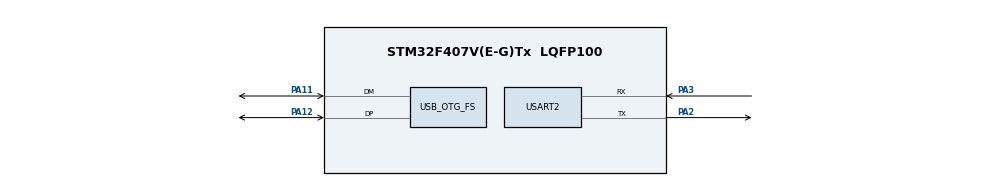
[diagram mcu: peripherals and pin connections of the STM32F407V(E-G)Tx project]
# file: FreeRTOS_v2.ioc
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FREERTOS.Tasks01=defaultTask,0,128,StartDefaultTask,Default,NULL,Dynamic,NULL,NULL
Mcu.Family=STM32F4
Mcu.Name=STM32F407V(E-G)Tx
Mcu.Package=LQFP100
NVIC.OTG_FS_IRQn=true\:5\:0\:false\:false\:true\:true\:false\:true\:true
NVIC.PriorityGroup=NVIC_PRIORITYGROUP_4
NVIC.TIM1_UP_TIM10_IRQn=true\:15\:0\:false\:false\:true\:false\:false\:true\:true
NVIC.TimeBase=TIM1_UP_TIM10_IRQn
NVIC.TimeBaseIP=TIM1
PA11.Mode=Device_Only
PA11.Signal=USB_OTG_FS_DM
PA12.Mode=Device_Only
PA12.Signal=USB_OTG_FS_DP
PA2.Mode=Asynchronous
PA2.Signal=USART2_TX
PA3.Mode=Asynchronous
PA3.Signal=USART2_RX
PC14-OSC32_IN.Mode=LSE-External-Oscillator
PC14-OSC32_IN.Signal=RCC_OSC32_IN
PC15-OSC32_OUT.Mode=LSE-External-Oscillator
PC15-OSC32_OUT.Signal=RCC_OSC32_OUT
PH0-OSC_IN.Mode=HSE-External-Oscillator
PH0-OSC_IN.Signal=RCC_OSC_IN
PH1-OSC_OUT.Mode=HSE-External-Oscillator
PH1-OSC_OUT.Signal=RCC_OSC_OUT
ProjectManager.HeapSize=0x200
ProjectManager.StackSize=0x400
ProjectManager.TargetToolchain=STM32CubeIDE
RCC.48MHZClocksFreq_Value=48000000
RCC.AHBFreq_Value=16000000
RCC.APB1Freq_Value=16000000
RCC.APB2Freq_Value=16000000
RCC.CortexFreq_Value=16000000
RCC.HSE_VALUE=8000000
RCC.HSI_VALUE=16000000
RCC.PLLM=4
RCC.PLLN=72
RCC.PLLQ=3
RCC.SYSCLKFreq_VALUE=16000000
RCC.VCOOutputFreq_Value=144000000
USART2.VirtualMode=VM_ASYNC
USB_DEVICE.CLASS_NAME_FS=CDC
USB_DEVICE.VirtualMode-CDC_FS=Cdc
USB_DEVICE.VirtualModeFS=Cdc_FS
USB_OTG_FS.VirtualMode=Device_Only
VP_FREERTOS_VS_CMSIS_V1.Mode=CMSIS_V1
VP_SYS_VS_tim1.Mode=TIM1
VP_USB_DEVICE_VS_USB_DEVICE_CDC_FS.Mode=CDC_FS
board=custom

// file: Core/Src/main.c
/* USER CODE BEGIN Header */
/**
  ******************************************************************************
  * @file           : main.c
  * @brief          : Main program body
  ******************************************************************************
  * @attention
  *
  * Copyright (c) 2026 STMicroelectronics.
  * All rights reserved.
  *
  * This software is licensed under terms that can be found in the LICENSE file
  * in the root directory of this software component.
  * If no LICENSE file comes with this software, it is provided AS-IS.
  *
  ******************************************************************************
  */

#include <stdio.h>
#include "uart.h"
#include "adc.h"
#include "exti.h"

/* USER CODE END Header */
#include "main.h"
#include "cmsis_os.h"
#include "usb_device.h"

/* USER CODE BEGIN PV */

/* Definitions for defaultTask */

/* USER CODE END PV */

void SystemClock_Config(void);
static void MX_GPIO_Init(void);

/* USER CODE BEGIN 0 */
void ADC_Task(void *pvParameters);
TaskHandle_t receiver_handle;
/* USER CODE END 0 */

int main(void)
{

  /* MCU Configuration--------------------------------------------------------*/

  /* Reset of all peripherals, Initializes the Flash interface and the Systick. */
  HAL_Init();

  /* Configure the system clock */
  SystemClock_Config();

  /* Initialize all configured peripherals */
  MX_GPIO_Init();
  MX_USART2_UART_TX_Init();
  MX_USART2_UART_RX_Init();
  /* USER CODE BEGIN 2 */
  MX_USB_DEVICE_Init();
  gpio_init();

  dmaSemaphore=xSemaphoreCreateBinary();

  adc_init();

  xTaskCreate(ADC_Task,"Receiver Task",500,NULL,2,&receiver_handle);
  vTaskStartScheduler();

  /* USER CODE END 2 */

  /* Create the thread(s) */

  /* Start scheduler */

  /* We should never get here as control is now taken by the scheduler */

  /* Infinite loop */
  while (1)
  {

  }
}

void SystemClock_Config(void)
{
  RCC_OscInitTypeDef RCC_OscInitStruct = {0};
  RCC_ClkInitTypeDef RCC_ClkInitStruct = {0};

  /** Configure the main internal regulator output voltage
  */
  __HAL_RCC_PWR_CLK_ENABLE();
  __HAL_PWR_VOLTAGESCALING_CONFIG(PWR_REGULATOR_VOLTAGE_SCALE1);

  /** Initializes the RCC Oscillators according to the specified parameters
  * in the RCC_OscInitTypeDef structure.
  */
  RCC_OscInitStruct.OscillatorType = RCC_OSCILLATORTYPE_HSI|RCC_OSCILLATORTYPE_HSE;
  RCC_OscInitStruct.HSEState = RCC_HSE_ON;
  RCC_OscInitStruct.HSIState = RCC_HSI_ON;
  RCC_OscInitStruct.HSICalibrationValue = RCC_HSICALIBRATION_DEFAULT;
  RCC_OscInitStruct.PLL.PLLState = RCC_PLL_ON;
  RCC_OscInitStruct.PLL.PLLSource = RCC_PLLSOURCE_HSE;
  RCC_OscInitStruct.PLL.PLLM = 4;
  RCC_OscInitStruct.PLL.PLLN = 72;
  RCC_OscInitStruct.PLL.PLLP = RCC_PLLP_DIV2;
  RCC_OscInitStruct.PLL.PLLQ = 3;
  if (HAL_RCC_OscConfig(&RCC_OscInitStruct) != HAL_OK)
  {
    Error_Handler();
  }

  /** Initializes the CPU, AHB and APB buses clocks
  */
  RCC_ClkInitStruct.ClockType = RCC_CLOCKTYPE_HCLK|RCC_CLOCKTYPE_SYSCLK
                              |RCC_CLOCKTYPE_PCLK1|RCC_CLOCKTYPE_PCLK2;
  RCC_ClkInitStruct.SYSCLKSource = RCC_SYSCLKSOURCE_PLLCLK;
  RCC_ClkInitStruct.AHBCLKDivider = RCC_SYSCLK_DIV1;
  RCC_ClkInitStruct.APB1CLKDivider = RCC_HCLK_DIV1;
  RCC_ClkInitStruct.APB2CLKDivider = RCC_HCLK_DIV1;

  if (HAL_RCC_ClockConfig(&RCC_ClkInitStruct, FLASH_LATENCY_2) != HAL_OK)
  {
    Error_Handler();
  }
}

static void MX_GPIO_Init(void)
{
  /* USER CODE BEGIN MX_GPIO_Init_1 */
	GPIO_InitTypeDef GPIO_InitStruct;
  /* USER CODE END MX_GPIO_Init_1 */

  /* GPIO Ports Clock Enable */
  __HAL_RCC_GPIOC_CLK_ENABLE();
  __HAL_RCC_GPIOH_CLK_ENABLE();
  __HAL_RCC_GPIOA_CLK_ENABLE();

  /* USER CODE BEGIN MX_GPIO_Init_2 */
  /* Enable Clock  access to port */
  __HAL_RCC_GPIOD_CLK_ENABLE();
  /* Reset PINS */
  HAL_GPIO_WritePin(GPIOD,GPIO_PIN_12|GPIO_PIN_13|GPIO_PIN_14|GPIO_PIN_15,GPIO_PIN_RESET);
  /* Configure PINS */
  GPIO_InitStruct.Pin = GPIO_PIN_12|GPIO_PIN_13|GPIO_PIN_14|GPIO_PIN_15;
  GPIO_InitStruct.Speed = GPIO_SPEED_FREQ_LOW;
  GPIO_InitStruct.Mode = GPIO_MODE_OUTPUT_PP;
  GPIO_InitStruct.Pull = GPIO_NOPULL;

  /* Initialize PINS */
  HAL_GPIO_Init(GPIOD, &GPIO_InitStruct);
  /* USER CODE END MX_GPIO_Init_2 */
}

  /* init code for USB_DEVICE */
  /* USER CODE END 5 */

void HAL_TIM_PeriodElapsedCallback(TIM_HandleTypeDef *htim)
{
  if (htim->Instance == TIM1)
  {
    HAL_IncTick();
  }
}

void Error_Handler(void)
{
  __disable_irq();
  while (1)
  {
  }
}

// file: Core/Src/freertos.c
/* USER CODE BEGIN Header */
/**
  ******************************************************************************
  * File Name          : freertos.c
  * Description        : Code for freertos applications
  ******************************************************************************
  * @attention
  *
  * Copyright (c) 2026 STMicroelectronics.
  * All rights reserved.
  *
  * This software is licensed under terms that can be found in the LICENSE file
  * in the root directory of this software component.
  * If no LICENSE file comes with this software, it is provided AS-IS.
  *
  ******************************************************************************
  */
/* USER CODE END Header */

#include "FreeRTOS.h"
#include "task.h"
#include "queue.h"
#include "main.h"

/* GetIdleTaskMemory prototype (linked to static allocation support) */
void vApplicationGetIdleTaskMemory( StaticTask_t **ppxIdleTaskTCBBuffer, StackType_t **ppxIdleTaskStackBuffer, uint32_t *pulIdleTaskStackSize );

/* USER CODE BEGIN GET_IDLE_TASK_MEMORY */
static StaticTask_t xIdleTaskTCBBuffer;
static StackType_t xIdleStack[configMINIMAL_STACK_SIZE];

void vApplicationGetIdleTaskMemory( StaticTask_t **ppxIdleTaskTCBBuffer, StackType_t **ppxIdleTaskStackBuffer, uint32_t *pulIdleTaskStackSize )
{
  *ppxIdleTaskTCBBuffer = &xIdleTaskTCBBuffer;
  *ppxIdleTaskStackBuffer = &xIdleStack[0];
  *pulIdleTaskStackSize = configMINIMAL_STACK_SIZE;
  /* place for user code */
}
/* USER CODE END GET_IDLE_TASK_MEMORY */
